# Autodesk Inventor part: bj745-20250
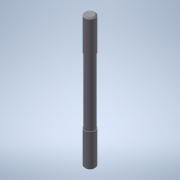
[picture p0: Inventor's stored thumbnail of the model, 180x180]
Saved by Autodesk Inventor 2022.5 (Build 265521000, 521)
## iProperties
Created: 2016-12
Part Number: bj745-20250
Material: 一般
Document SubType Name: Modeling
Designer: imaocorp
Density: 1 g/cm^3
Appearance: 既定
Author: imaocorp
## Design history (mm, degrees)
node "bj745-20250.x_t1"
node "bj745-20250"
node "Base1"
